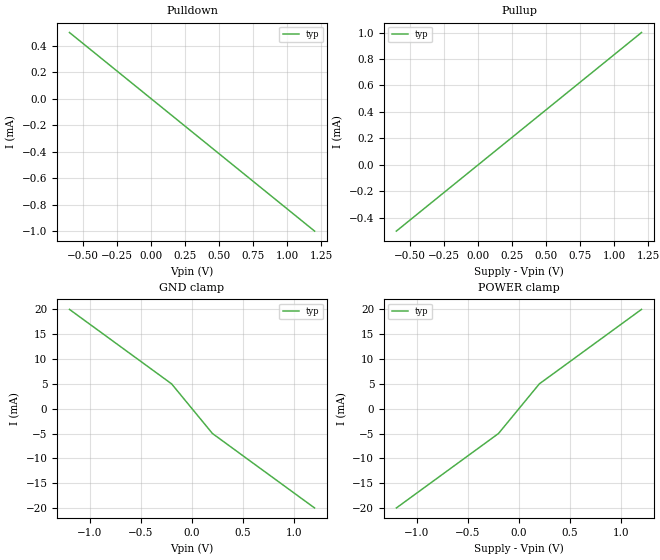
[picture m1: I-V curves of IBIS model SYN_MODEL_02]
[IBIS Ver] 7.2
[File Name] SYN_MODEL_02.ibs
[File Rev] 1.0
[Date] 07-NOV-2025
[Source] Synthetic IBIS models for testing
[Disclaimer] For educational and testing use only
[Component] SYN_COMP_02
[Manufacturer] OpenSim Labs
[Package]
R_pkg = 0.066
L_pkg = 2.53e-09
C_pkg = 3.3e-12
[Pin] signal_name model_name R_pin L_pin C_pin
1   IO1   SYN_MODEL_02   0.0   0.0   0.0
2   VCC   POWER   0.0   0.0   0.0
3   GND   GND   0.0   0.0   0.0
| Models and submodels in the file (1): SYN_MODEL_02 (i/o)
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[Model] SYN_MODEL_02
Model_type i/o
Polarity   Non-Inverting
Enable   Active-High
Vinh   0.66
Vinl   0.3
Vref   0.6
C_comp   2.99pF
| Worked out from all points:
|   GND clamp passes 1 mA (typ) near -0.04 V on its own axis
|   POWER clamp passes 1 mA (typ) near -0.04 V on its own axis
| IV tables
[Pullup]
|V (V)   I (A)
-600mV    -500uA     NA         NA
0V        0A         NA         NA
600mV     500uA      NA         NA
1.2V      1mA        NA         NA
[Pulldown]
|V (V)   I (A)
-600mV    500uA      NA         NA
0V        0A         NA         NA
600mV     -500uA     NA         NA
1.2V      -1mA       NA         NA
[GND Clamp]
|V (V)   I (A)
-1.2V     20mA       NA         NA
-200mV    5mA        NA         NA
0V        0A         NA         NA
200mV     -5mA       NA         NA
1.2V      -20mA      NA         NA
[POWER Clamp]
|V (V)   I (A)
-1.2V     -20mA      NA         NA
-200mV    -5mA       NA         NA
0V        0A         NA         NA
200mV     5mA        NA         NA
1.2V      20mA       NA         NA
| Dynamic behavior
[Voltage Time]
R_fixture 50.0
V_fixture 1.200
| Rising Waveform
|t (s)   V (V)
 0.000e+00   0.000000
 1.031e-10   0.360000
 2.062e-10   0.720000
 3.094e-10   1.020000
 4.125e-10   1.200000
[Voltage Time]
R_fixture 50.0
V_fixture 1.200
| Falling Waveform
|t (s)   V (V)
 0.000e+00   1.200000
 9.070e-11   0.840000
 1.814e-10   0.480000
 2.721e-10   0.180000
 3.628e-10   0.000000
